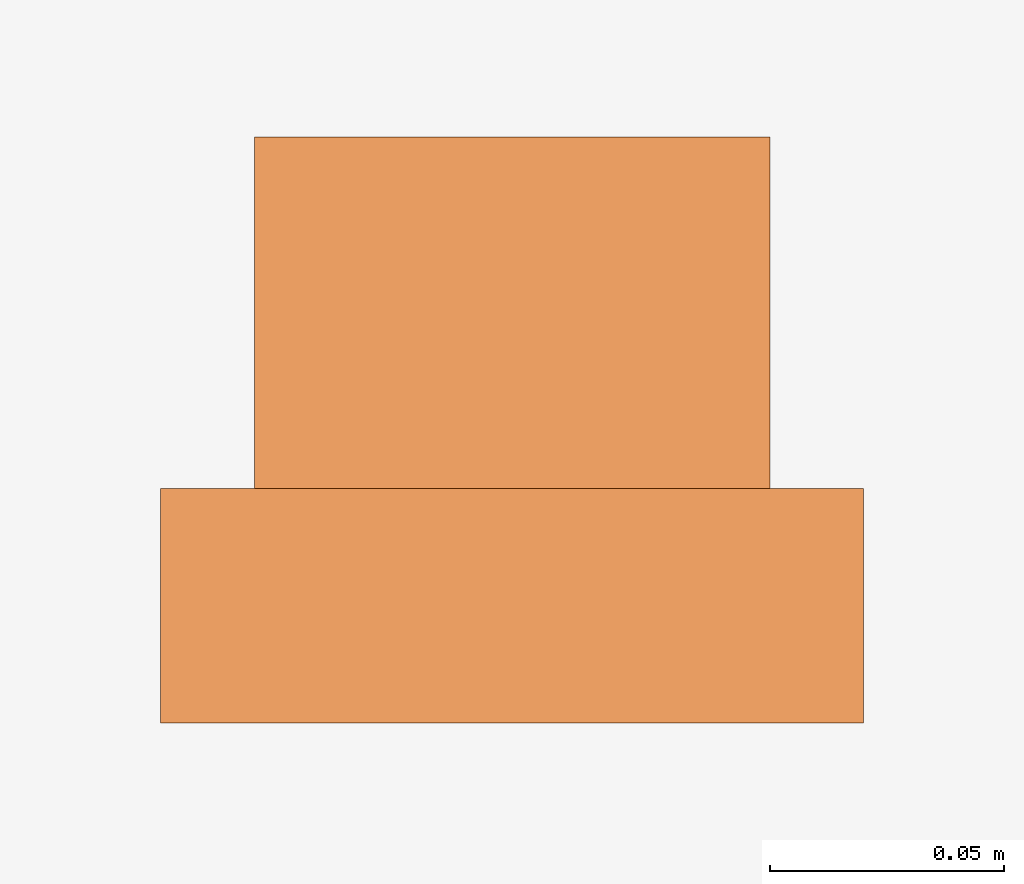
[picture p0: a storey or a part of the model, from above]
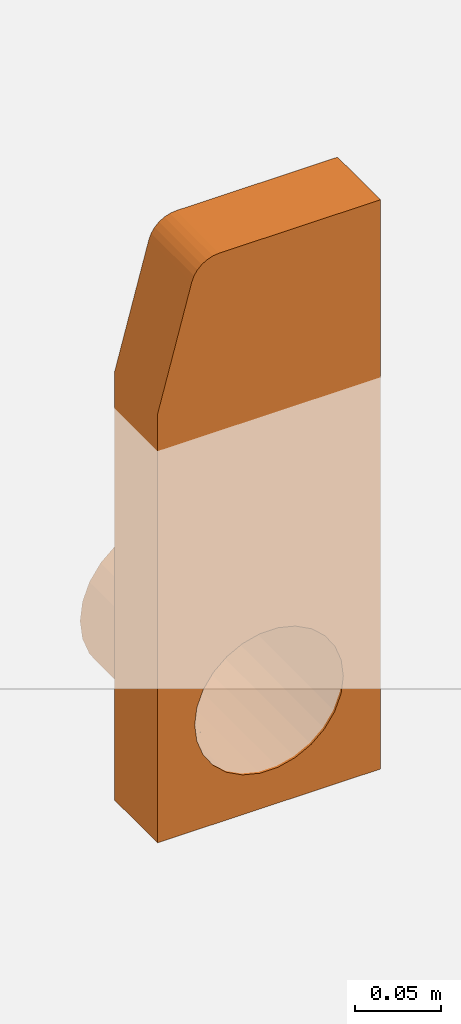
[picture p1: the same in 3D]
Properties of the parts of a building model (IFC2X3)

# File
Description: ViewDefinition [CoordinationView]
File name: 4237 - LH inlet-outlet end cap.ifc
Time: 2013-09-02T12:43:14
Written by: Autodesk Revit 2013
Made in: 20120221_2030(x64)

# IfcProject, Project Number
LongName: Project Name; Phase: Project Status

# IfcSite, Default
RefLatitude: 42, 21, 30, 344238; RefLongitude: -71, -3, -35, -194702; RefElevation: 0 mm

# IfcBuilding
Pset_BuildingCommon - NumberOfStoreys: 1
Other - Project Status: Project Status; Project Address: ## Street City, State Zip; Project Number: Project Number; Client Name: Owner; Project Name: Project Name; Project Issue Date: Issue Date

# IfcBuildingStorey, Level 1
LongName: Level 1; Elevation: 0 mm
Constraints - Elevation Base: 0; Elevation: 0 mm
Graphics - Symbol at End 1 Default: no; Line Weight: 1; Color: 0; Symbol at End 2 Default: yes; Line Pattern: Center; Symbol: M_Level Head - Circle: M_Level Head - Circle
Identity Data - Building Story: yes; Structural: no; Name: Level 1
Dimensions - Computation Height: 0 mm

# IfcBuildingElementProxy: 4237 - LH inlet/outlet end cap, Civil-Drainage-Channel-ACO-KerbDrain-HB405:4237 - LH inlet/outlet end cap:4237 - LH inlet/outlet end cap:312781
In: Level 1
Material: Orange, ACO Polymer Concrete.
Constraints - Level: Level: Level 1; Moves With Nearby Elements: no
Dimensions - Volume: 2699489 mm3; Void Depth: -280 mm; Void Length: 50 mm; Circular Void Depth: 329.966 mm; Void Width: 150 mm
Phasing - Phase Created: New Construction
Pset_BuildingElementProxyCommon - Reference: 4237 - LH inlet/outlet end cap
Identity Data - Address: ACO Business Park, Hitchin Road, Shefford, Bedfordshire, United Kingdom SG17 5TE; Fax: +44 (0)1462 815895; Type Comments: ACO KerbDrain HB405 half battered LH outlet end cap; Model Description: Combined kerb and drainage system; Model: ACO KerbDrain HB405; e-mail Sales: customersupport@aco.co.uk; Product Page URL: http://www.aco.co.uk/product_detail.php?id=3; Cost: 0; Product Code: 4237; Installation guidelines: http://www.aco.co.uk/download.php?id=120; Telephone: +44 (0)1462 816666; URL: www.aco.co.uk; OmniClass Title: Rainwater Removal; Manufacturer: ACO Technologies plc - ACO Water Management Division; Maintenance guidelines: http://www.aco.co.uk/download.php?id=120; e-mail Technical: technical@aco.co.uk; OmniClass Number: 23.70.50.24; Product brochure: http://www.aco.co.uk/download.php?id=120; Price: POA - contact ACO; Assembly Code: D2040; Assembly Description: Rain Water Drainage
Other - CreatedBy: www.aco.co.uk; Revision: 1
Data - Product Standard: N/A; Concrete Surround Volume - Load Class A 15 - D 400 - Concrete Pavement: N/A; Drainage Slot Width: N/A; Product Weight: 5.7 Kg; Channel C.S.A: N/A; Concrete Surround Volume - Load Class A 15 - D 400 - Grass or Asphalt Pavement: N/A; Load Class: N/A; Invert Depth: N/A; Hydraulic Performance: N/A; Drainage Slot Intake area: N/A; ACO Hydraulic Design Software: N/A; Installation - Concrete Grade: N/A; Product Dimensions: 50mm x 150mm x 405mm (LxWxH); Connection Pipe O.D: Ø110mm
Materials and Finishes - Access Cover/Frame Material: N/A; Access Cover/Frame Colour: N/A; Connection Pipe Material: PVCu; Channel Material: N/A; Access Cover/Frame Finish: N/A; Channel Colour: N/A; End Cap Colour: Grey; End Cap Material: Vienite® Synthetic Resin Concrete; Connection Pipe Material Colour: Brown
Construction - LH drop kerb: no; LH inlet/outlet end cap: yes; Closing end cap: no; HB405 500_blindunit: no; HB405 - 1000: no; Centre Stone: no; HB405 - 500: no; Access Unit: no; RH inlet/outlet end cap: no; RH drop kerb: no
General - TagNumber: 0.000000; SerialNumber: 0.000000
Green Building Properties - Access Cover/Frame Recyclable: N/A; Channel Recyclable: N/A; Channel Recycled Material Content: N/A; End Cap Recycled Material Content: 20% minimum; End Cap Recyclable: Fully recyclable; Access Cover/Frame Recycled Material Content: N/A

# IfcOpeningElement: Recess
In: Level 1
Constraints - Height Offset From Level: 0 mm; Room Bounding: yes; Level: Level: Level 1; Related to Mass: no
Dimensions - Area: 151470000 mm2; Perimeter: 51360 mm; Thickness: 400 mm; Volume: 60585191728 mm3
Structural - Structural: no; Enable Analytical Model: no
Phasing - Phase Created: New Construction
Graphics - Coarse Scale Fill Color: 0
Construction - Default Thickness: 400 mm; Function: 0
Materials and Finishes - Structural Material: Plant
Analytical Properties - Absorptance: 0.1; Roughness: 1

# IfcSlab: Floor:Generic Floor - 400mm, Floor:Generic Floor - 400mm:193825
In: Level 1
PredefinedType: FLOOR; Material: Plant 400 mm
Constraints - Height Offset From Level: 0 mm; Room Bounding: yes; Level: Level: Level 1; Related to Mass: no
Dimensions - Area: 151470000 mm2; Perimeter: 51360 mm; Thickness: 400 mm; Volume: 60585191728 mm3
Structural - Structural: no; Enable Analytical Model: no
Phasing - Phase Created: New Construction
Pset_SlabCommon - Reference: Generic Floor - 400mm; IsExternal: no; LoadBearing: yes
Graphics - Coarse Scale Fill Color: 0
Construction - Default Thickness: 400 mm; Function: 0
Materials and Finishes - Structural Material: Plant
Analytical Properties - Absorptance: 0.1; Roughness: 1
